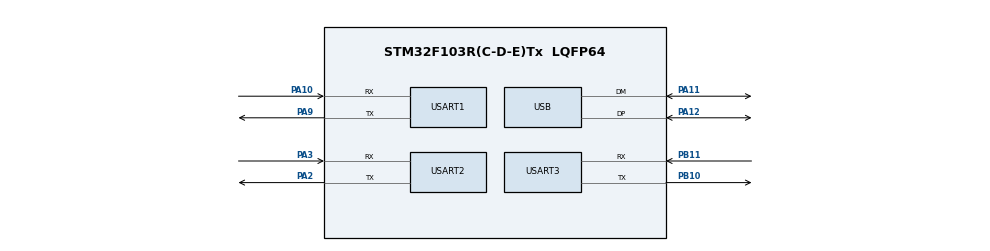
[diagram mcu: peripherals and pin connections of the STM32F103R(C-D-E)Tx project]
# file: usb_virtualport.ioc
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Dma.Request0=USART1_RX
Dma.Request1=USART1_TX
Dma.Request2=USART2_RX
Dma.Request3=USART2_TX
Dma.Request4=USART3_RX
Dma.Request5=USART3_TX
Dma.USART1_RX.0.Direction=DMA_PERIPH_TO_MEMORY
Dma.USART1_RX.0.Instance=DMA1_Channel5
Dma.USART1_RX.0.MemDataAlignment=DMA_MDATAALIGN_BYTE
Dma.USART1_RX.0.MemInc=DMA_MINC_ENABLE
Dma.USART1_RX.0.Mode=DMA_NORMAL
Dma.USART1_RX.0.PeriphDataAlignment=DMA_PDATAALIGN_BYTE
Dma.USART1_RX.0.PeriphInc=DMA_PINC_DISABLE
Dma.USART1_RX.0.Priority=DMA_PRIORITY_LOW
Dma.USART1_TX.1.Direction=DMA_MEMORY_TO_PERIPH
Dma.USART1_TX.1.Instance=DMA1_Channel4
Dma.USART1_TX.1.MemDataAlignment=DMA_MDATAALIGN_BYTE
Dma.USART1_TX.1.MemInc=DMA_MINC_ENABLE
Dma.USART1_TX.1.Mode=DMA_NORMAL
Dma.USART1_TX.1.PeriphDataAlignment=DMA_PDATAALIGN_BYTE
Dma.USART1_TX.1.PeriphInc=DMA_PINC_DISABLE
Dma.USART1_TX.1.Priority=DMA_PRIORITY_LOW
Dma.USART2_RX.2.Direction=DMA_PERIPH_TO_MEMORY
Dma.USART2_RX.2.Instance=DMA1_Channel6
Dma.USART2_RX.2.MemDataAlignment=DMA_MDATAALIGN_BYTE
Dma.USART2_RX.2.MemInc=DMA_MINC_ENABLE
Dma.USART2_RX.2.Mode=DMA_NORMAL
Dma.USART2_RX.2.PeriphDataAlignment=DMA_PDATAALIGN_BYTE
Dma.USART2_RX.2.PeriphInc=DMA_PINC_DISABLE
Dma.USART2_RX.2.Priority=DMA_PRIORITY_LOW
Dma.USART2_TX.3.Direction=DMA_MEMORY_TO_PERIPH
Dma.USART2_TX.3.Instance=DMA1_Channel7
Dma.USART2_TX.3.MemDataAlignment=DMA_MDATAALIGN_BYTE
Dma.USART2_TX.3.MemInc=DMA_MINC_ENABLE
Dma.USART2_TX.3.Mode=DMA_NORMAL
Dma.USART2_TX.3.PeriphDataAlignment=DMA_PDATAALIGN_BYTE
Dma.USART2_TX.3.PeriphInc=DMA_PINC_DISABLE
Dma.USART2_TX.3.Priority=DMA_PRIORITY_LOW
Dma.USART3_RX.4.Direction=DMA_PERIPH_TO_MEMORY
Dma.USART3_RX.4.Instance=DMA1_Channel3
Dma.USART3_RX.4.MemDataAlignment=DMA_MDATAALIGN_BYTE
Dma.USART3_RX.4.MemInc=DMA_MINC_ENABLE
Dma.USART3_RX.4.Mode=DMA_NORMAL
Dma.USART3_RX.4.PeriphDataAlignment=DMA_PDATAALIGN_BYTE
Dma.USART3_RX.4.PeriphInc=DMA_PINC_DISABLE
Dma.USART3_RX.4.Priority=DMA_PRIORITY_LOW
Dma.USART3_TX.5.Direction=DMA_MEMORY_TO_PERIPH
Dma.USART3_TX.5.Instance=DMA1_Channel2
Dma.USART3_TX.5.MemDataAlignment=DMA_MDATAALIGN_BYTE
Dma.USART3_TX.5.MemInc=DMA_MINC_ENABLE
Dma.USART3_TX.5.Mode=DMA_NORMAL
Dma.USART3_TX.5.PeriphDataAlignment=DMA_PDATAALIGN_BYTE
Dma.USART3_TX.5.PeriphInc=DMA_PINC_DISABLE
Dma.USART3_TX.5.Priority=DMA_PRIORITY_LOW
FREERTOS.Tasks01=defaultTask,0,128,StartDefaultTask,Default,NULL,Dynamic,NULL,NULL
Mcu.Family=STM32F1
Mcu.Name=STM32F103R(C-D-E)Tx
Mcu.Package=LQFP64
NVIC.DMA1_Channel2_IRQn=true\:5\:0\:false\:false\:true\:true\:false\:true\:true
NVIC.DMA1_Channel3_IRQn=true\:5\:0\:false\:false\:true\:true\:false\:true\:true
NVIC.DMA1_Channel4_IRQn=true\:5\:0\:false\:false\:true\:true\:false\:true\:true
NVIC.DMA1_Channel5_IRQn=true\:5\:0\:false\:false\:true\:true\:false\:true\:true
NVIC.DMA1_Channel6_IRQn=true\:5\:0\:false\:false\:true\:true\:false\:true\:true
NVIC.DMA1_Channel7_IRQn=true\:5\:0\:false\:false\:true\:true\:false\:true\:true
NVIC.PriorityGroup=NVIC_PRIORITYGROUP_4
NVIC.USART1_IRQn=true\:5\:0\:false\:false\:true\:true\:true\:true\:true
NVIC.USART2_IRQn=true\:5\:0\:false\:false\:true\:true\:true\:true\:true
NVIC.USART3_IRQn=true\:5\:0\:false\:false\:true\:true\:true\:true\:true
NVIC.USB_HP_CAN1_TX_IRQn=true\:5\:0\:false\:false\:true\:true\:true\:true\:true
NVIC.USB_LP_CAN1_RX0_IRQn=true\:5\:0\:false\:false\:true\:true\:false\:true\:true
PA10.Mode=Asynchronous
PA10.Signal=USART1_RX
PA11.Mode=Device
PA11.Signal=USB_DM
PA12.Mode=Device
PA12.Signal=USB_DP
PA13.Mode=Serial_Wire
PA13.Signal=SYS_JTMS-SWDIO
PA14.Mode=Serial_Wire
PA14.Signal=SYS_JTCK-SWCLK
PA2.Mode=Asynchronous
PA2.Signal=USART2_TX
PA3.Mode=Asynchronous
PA3.Signal=USART2_RX
PA9.Mode=Asynchronous
PA9.Signal=USART1_TX
PB10.Mode=Asynchronous
PB10.Signal=USART3_TX
PB11.Mode=Asynchronous
PB11.Signal=USART3_RX
PD0-OSC_IN.Mode=HSE-External-Oscillator
PD0-OSC_IN.Signal=RCC_OSC_IN
PD1-OSC_OUT.Mode=HSE-External-Oscillator
PD1-OSC_OUT.Signal=RCC_OSC_OUT
ProjectManager.HeapSize=0x1000
ProjectManager.StackSize=0x1000
ProjectManager.TargetToolchain=MDK-ARM V5.32
RCC.AHBFreq_Value=72000000
RCC.APB1CLKDivider=RCC_HCLK_DIV2
RCC.APB1Freq_Value=36000000
RCC.APB1TimFreq_Value=72000000
RCC.APB2Freq_Value=72000000
RCC.APB2TimFreq_Value=72000000
RCC.HCLKFreq_Value=72000000
RCC.HSEDivPLL=RCC_HSE_PREDIV_DIV2
RCC.HSE_VALUE=16000000
RCC.PLLMUL=RCC_PLL_MUL9
RCC.PLLSourceVirtual=RCC_PLLSOURCE_HSE
RCC.SYSCLKFreq_VALUE=72000000
RCC.SYSCLKSource=RCC_SYSCLKSOURCE_PLLCLK
RCC.USBFreq_Value=48000000
RCC.USBPrescaler=RCC_USBCLKSOURCE_PLL_DIV1_5
USART1.VirtualMode=VM_ASYNC
USART2.VirtualMode=VM_ASYNC
USART3.VirtualMode=VM_ASYNC
USB_DEVICE.CLASS_NAME_FS=CDC
USB_DEVICE.VirtualMode=Cdc
USB_DEVICE.VirtualModeFS=Cdc_FS
VP_FREERTOS_VS_CMSIS_V1.Mode=CMSIS_V1
VP_USB_DEVICE_VS_USB_DEVICE_CDC_FS.Mode=CDC_FS
board=custom

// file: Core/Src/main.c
/* USER CODE BEGIN Header */
/**
  ******************************************************************************
  * @file           : main.c
  * @brief          : Main program body
  ******************************************************************************
  * @attention
  *
  * Copyright (c) 2023 STMicroelectronics.
  * All rights reserved.
  *
  * This software is licensed under terms that can be found in the LICENSE file
  * in the root directory of this software component.
  * If no LICENSE file comes with this software, it is provided AS-IS.
  *
  ******************************************************************************
  */
/* USER CODE END Header */
#include "main.h"
#include "cmsis_os.h"
#include "dma.h"
#include "usart.h"
#include "usb_device.h"
#include "gpio.h"

/* USER CODE BEGIN Includes */
#include "usbd_cdc_if.h"
/* USER CODE END Includes */

void SystemClock_Config(void);
void MX_FREERTOS_Init(void);

/* USER CODE BEGIN 0 */
User_Uart_Parameter user_param_uart[3];
/* USER CODE END 0 */

int main(void)
{

  /* MCU Configuration--------------------------------------------------------*/

  /* Reset of all peripherals, Initializes the Flash interface and the Systick. */
  HAL_Init();

  /* Configure the system clock */
  SystemClock_Config();

  /* Initialize all configured peripherals */
  MX_GPIO_Init();
  MX_DMA_Init();
  MX_USB_DEVICE_Init();
  MX_USART1_UART_Init();
  MX_USART2_UART_Init();
  MX_USART3_UART_Init();

  /* Call init function for freertos objects (in freertos.c) */
  MX_FREERTOS_Init();

  /* Start scheduler */
  osKernelStart();

  /* We should never get here as control is now taken by the scheduler */
  /* Infinite loop */
  while (1)
  {

  }
}

void SystemClock_Config(void)
{
  RCC_OscInitTypeDef RCC_OscInitStruct = {0};
  RCC_ClkInitTypeDef RCC_ClkInitStruct = {0};
  RCC_PeriphCLKInitTypeDef PeriphClkInit = {0};

  /** Initializes the RCC Oscillators according to the specified parameters
  * in the RCC_OscInitTypeDef structure.
  */
  RCC_OscInitStruct.OscillatorType = RCC_OSCILLATORTYPE_HSE;
  RCC_OscInitStruct.HSEState = RCC_HSE_ON;
  RCC_OscInitStruct.HSEPredivValue = RCC_HSE_PREDIV_DIV1;
  RCC_OscInitStruct.HSIState = RCC_HSI_ON;
  RCC_OscInitStruct.PLL.PLLState = RCC_PLL_ON;
  RCC_OscInitStruct.PLL.PLLSource = RCC_PLLSOURCE_HSE;
  RCC_OscInitStruct.PLL.PLLMUL = RCC_PLL_MUL9;
  if (HAL_RCC_OscConfig(&RCC_OscInitStruct) != HAL_OK)
  {
    Error_Handler();
  }

  /** Initializes the CPU, AHB and APB buses clocks
  */
  RCC_ClkInitStruct.ClockType = RCC_CLOCKTYPE_HCLK|RCC_CLOCKTYPE_SYSCLK
                              |RCC_CLOCKTYPE_PCLK1|RCC_CLOCKTYPE_PCLK2;
  RCC_ClkInitStruct.SYSCLKSource = RCC_SYSCLKSOURCE_PLLCLK;
  RCC_ClkInitStruct.AHBCLKDivider = RCC_SYSCLK_DIV1;
  RCC_ClkInitStruct.APB1CLKDivider = RCC_HCLK_DIV2;
  RCC_ClkInitStruct.APB2CLKDivider = RCC_HCLK_DIV1;

  if (HAL_RCC_ClockConfig(&RCC_ClkInitStruct, FLASH_LATENCY_2) != HAL_OK)
  {
    Error_Handler();
  }
  PeriphClkInit.PeriphClockSelection = RCC_PERIPHCLK_USB;
  PeriphClkInit.UsbClockSelection = RCC_USBCLKSOURCE_PLL_DIV1_5;
  if (HAL_RCCEx_PeriphCLKConfig(&PeriphClkInit) != HAL_OK)
  {
    Error_Handler();
  }
}

void Error_Handler(void)
{
  __disable_irq();
  while (1)
  {
  }
}

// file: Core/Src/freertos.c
/* USER CODE BEGIN Header */
/**
  ******************************************************************************
  * File Name          : freertos.c
  * Description        : Code for freertos applications
  ******************************************************************************
  * @attention
  *
  * Copyright (c) 2023 STMicroelectronics.
  * All rights reserved.
  *
  * This software is licensed under terms that can be found in the LICENSE file
  * in the root directory of this software component.
  * If no LICENSE file comes with this software, it is provided AS-IS.
  *
  ******************************************************************************
  */
/* USER CODE END Header */

#include "FreeRTOS.h"
#include "task.h"
#include "main.h"
#include "cmsis_os.h"

/* USER CODE BEGIN Includes */
#include "usbd_cdc_if.h"
/* USER CODE END Includes */

/* USER CODE BEGIN PD */

EventGroupHandle_t *UartRcvEventGroup;

/* USER CODE END PD */

osThreadId defaultTaskHandle;

/* USER CODE BEGIN FunctionPrototypes */
void UserDisplayTask(void const * argument);
/* USER CODE END FunctionPrototypes */

void StartDefaultTask(void const * argument);

extern void MX_USB_DEVICE_Init(void);
void MX_FREERTOS_Init(void); /* (MISRA C 2004 rule 8.1) */

/* GetIdleTaskMemory prototype (linked to static allocation support) */
void vApplicationGetIdleTaskMemory( StaticTask_t **ppxIdleTaskTCBBuffer, StackType_t **ppxIdleTaskStackBuffer, uint32_t *pulIdleTaskStackSize );

/* USER CODE BEGIN GET_IDLE_TASK_MEMORY */
static StaticTask_t xIdleTaskTCBBuffer;
static StackType_t xIdleStack[configMINIMAL_STACK_SIZE];

void vApplicationGetIdleTaskMemory( StaticTask_t **ppxIdleTaskTCBBuffer, StackType_t **ppxIdleTaskStackBuffer, uint32_t *pulIdleTaskStackSize )
{
  *ppxIdleTaskTCBBuffer = &xIdleTaskTCBBuffer;
  *ppxIdleTaskStackBuffer = &xIdleStack[0];
  *pulIdleTaskStackSize = configMINIMAL_STACK_SIZE;
  /* place for user code */
}
/* USER CODE END GET_IDLE_TASK_MEMORY */

void MX_FREERTOS_Init(void) {
  /* USER CODE BEGIN Init */
  UartRcvEventGroup = xEventGroupCreate();
  /* USER CODE END Init */

  /* Create the thread(s) */
  /* definition and creation of defaultTask */
  osThreadDef(defaultTask, StartDefaultTask, osPriorityNormal, 0, 128);
  defaultTaskHandle = osThreadCreate(osThread(defaultTask), NULL);

  /* USER CODE BEGIN RTOS_THREADS */
  /* add threads, ... */
    osThreadDef(userTask01, UserDisplayTask, osPriorityNormal, 0, 128);
  defaultTaskHandle = osThreadCreate(osThread(userTask01), NULL);
  /* USER CODE END RTOS_THREADS */

}

extern User_Uart_Parameter user_param_uart[3];
void StartDefaultTask(void const * argument)
{
  /* init code for USB_DEVICE */
//  MX_USB_DEVICE_Init();
  /* USER CODE BEGIN StartDefaultTask */
	EventBits_t xEventGroupValue;
	const EventBits_t xBitsToWaitFor = ( UART1_RECV_BIT | UART2_RECV_BIT | UART3_RECV_BIT );
  /* Infinite loop */
  for(;;)
  {
 #if 1
	if( set == user_param_uart[0].flag.bits.rx_down )
	{
		memcpy(UserTxBufferFS, user_param_uart[0].rx_buff, user_param_uart[0].rx_len);
		CDC_Transmit_FS(UserTxBufferFS, user_param_uart[0].rx_len, CDC_IN_EP);
		user_param_uart[0].flag.bits.rx_down = clear;
	}
	if( set == user_param_uart[1].flag.bits.rx_down )
	{
		memcpy(UserTxBufferFS, user_param_uart[1].rx_buff, user_param_uart[1].rx_len);
		CDC_Transmit_FS(UserTxBufferFS, user_param_uart[1].rx_len, CDC_IN_EP1);
		user_param_uart[1].flag.bits.rx_down = clear;
	}
	if( set == user_param_uart[2].flag.bits.rx_down )
	{
		memcpy(UserTxBufferFS, user_param_uart[2].rx_buff, user_param_uart[2].rx_len);
		CDC_Transmit_FS(UserTxBufferFS, user_param_uart[2].rx_len, CDC_IN_EP2);
		user_param_uart[2].flag.bits.rx_down = clear;
	}
    osDelay(1);
#else
	xEventGroupValue = xEventGroupWaitBits(     UartRcvEventGroup,	/* 事件组的句柄 */
												xBitsToWaitFor,		/* 待测试的事件位 */
												pdTRUE,				/* 满足添加时清除上面的事件位 */
												pdFALSE, 			/* 任意事件位被设置就会退出阻塞态 */
												portMAX_DELAY );	/* 没有超时 */

	if( set == ( xEventGroupValue & UART1_RECV_BIT ) )
	{
		memcpy(UserTxBufferFS, user_param_uart[0].rx_buff, user_param_uart[0].rx_len);
		CDC_Transmit_FS(UserTxBufferFS, user_param_uart[0].rx_len, CDC_IN_EP);
	}
	if( set == ( xEventGroupValue & UART2_RECV_BIT ) )
	{
		memcpy(UserTxBufferFS, user_param_uart[1].rx_buff, user_param_uart[1].rx_len);
		CDC_Transmit_FS(UserTxBufferFS, user_param_uart[1].rx_len, CDC_IN_EP1);
	}
	if( set == ( xEventGroupValue & UART3_RECV_BIT ) )
	{
		memcpy(UserTxBufferFS, user_param_uart[2].rx_buff, user_param_uart[2].rx_len);
		CDC_Transmit_FS(UserTxBufferFS, user_param_uart[2].rx_len, CDC_IN_EP2);
	}

#endif
  }
  /* USER CODE END StartDefaultTask */
}

/* USER CODE BEGIN Application */
void UserDisplayTask(void const * argument)
{
  /* init code for USB_DEVICE */
//  MX_USB_DEVICE_Init();
  /* USER CODE BEGIN StartDefaultTask */
  /* Infinite loop */
  for(;;)
  {
    HAL_GPIO_WritePin(GPIOB, LED_GREEN_Pin, GPIO_PIN_SET);
    osDelay(500);
    HAL_GPIO_WritePin(GPIOB, LED_GREEN_Pin, GPIO_PIN_RESET);
    osDelay(1);
  }
  /* USER CODE END StartDefaultTask */
}

/* USER CODE END Application */
